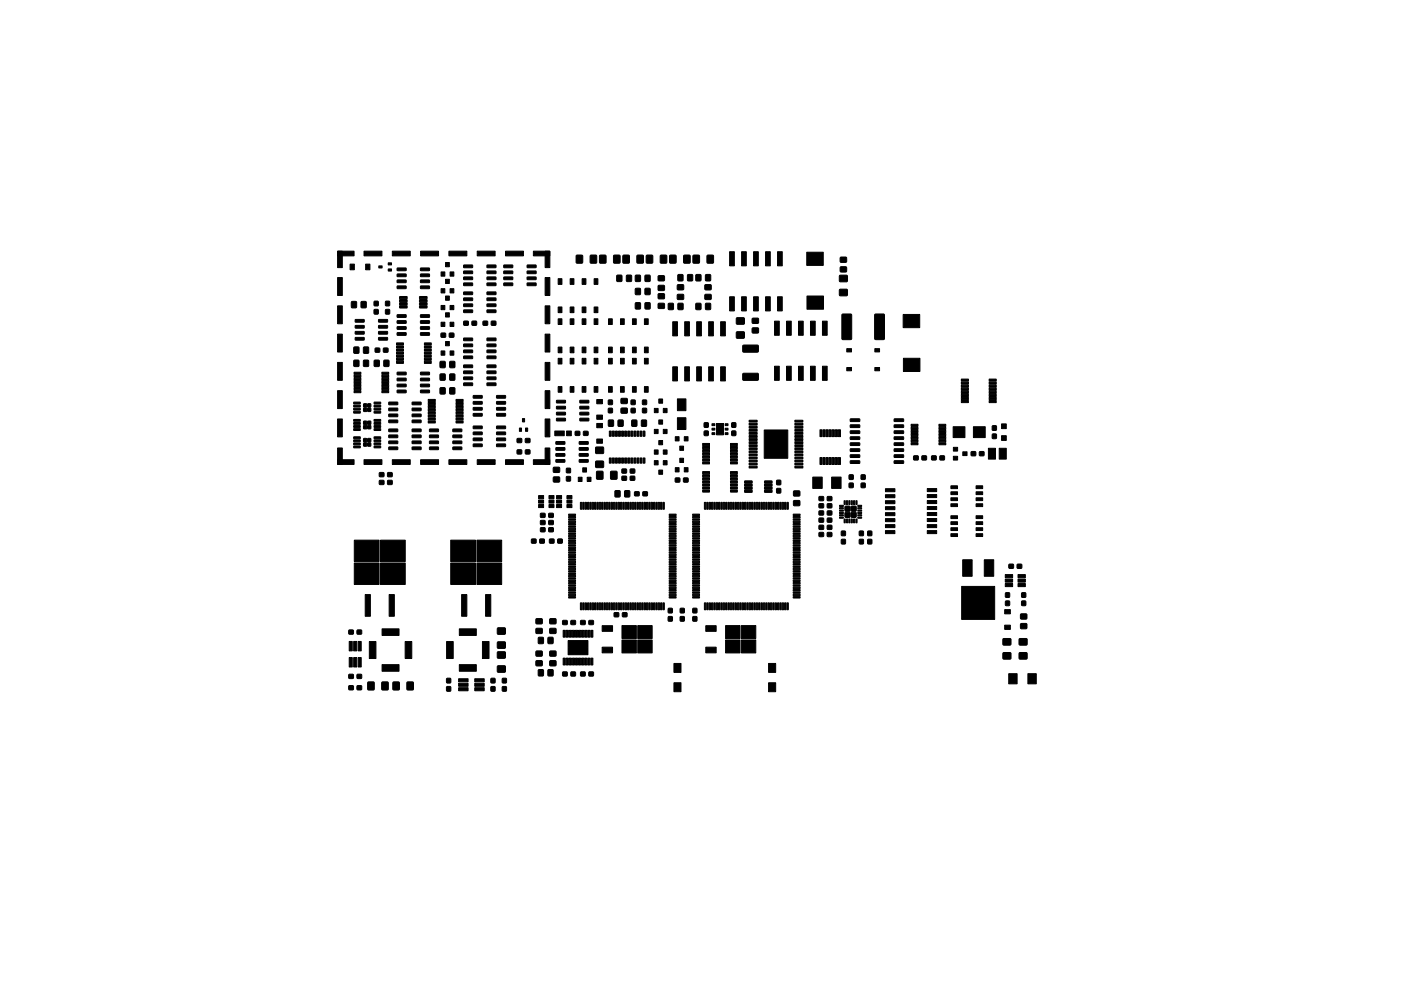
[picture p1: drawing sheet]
<svg xmlns="http://www.w3.org/2000/svg" width="297mm" height="210mm" viewBox="0 0 297 210" stroke-linecap="round" stroke-linejoin="round" font-family="sans-serif">
<g fill="#000" stroke="#000" stroke-width=".21">
<path d="M71.6 53.3h1v3.5h-1zM74.2 56h.9v1.2h-.9zM71.6 53.3h3.5v1h-3.5zM77.5 56h.9v1.2h-.9zM77.2 53.3h3.8v1h-3.8zM80.3 56.4h.7v.5h-.7zM82.3 55.8h.7v.4h-.7zM82.3 57.1h.7v.4h-.7zM84.2 59.4h1.8l.1 .5-.1 .1h-1.7zM84.2 58.2l1.8-.1 .1 .5-.1 .1h-1.7zM84.2 56.9l1.8-.1 .1 .5-.1 .1h-1.7zM83.2 53.3h3.8v1h-3.8z"/>
<path d="M89.2 56.9l1.8-.1 .1 .5-.2 .1h-1.6zM89.2 58.2l1.8-.1 .1 .5-.2 .1h-1.6zM89.2 59.4h1.8l.1 .5-.2 .1h-1.6zM89.2 53.3h3.8v1h-3.8zM93.5 57.7h.8v.9h-.8zM94.5 55.7h.8v.9h-.8zM95.4 57.7h.8v.9h-.8zM95.2 53.3h3.8v1h-3.8zM98.3 58.8h1.8l.1 .4-.1 .1h-1.7zM98.3 57.5h1.8l.1 .5-.1 .1h-1.7zM98.3 56.3l1.8-.1 .1 .5-.1 .1h-1.7zM101.2 53.3h3.8v1h-3.8z"/>
<path d="M103.3 56.3l1.8-.1 .1 .5-.2 .1h-1.7zM103.3 57.5h1.8l.1 .5-.2 .1h-1.7zM103.3 58.8h1.8l.1 .4-.2 .1h-1.7zM106.8 58.8h1.8l.1 .4-.1 .1h-1.7zM106.8 57.5h1.8l.1 .5-.1 .1h-1.7zM106.8 56.3l1.8-.1 .1 .5-.1 .1h-1.7zM107.2 53.3h3.8v1h-3.8zM111.8 56.3l1.8-.1 .1 .5-.1 .1h-1.7zM111.8 57.5h1.8l.1 .5-.1 .1h-1.7zM111.8 58.8h1.8l.1 .4-.1 .1h-1.7zM115.6 53.3h1v3.5h-1zM113.1 53.3h3.5v1h-3.5z"/>
<path d="M122.2 54.2h1.3v1.6h-1.3zM125.2 54.2h1.3l-.1 1.6h-1.2zM127.2 54.2h1.3l-.1 1.6h-1.3zM130.1 54.2h1.3v1.6h-1.3zM130.8 58.4h1v1.3h-1zM132.1 54.2h1.3v1.6h-1.3zM132.9 58.4h1l-.1 1.3h-1zM134.7 58.4h1.1l-.1 1.3h-1zM135.1 54.2h1.3l-.1 1.6h-1.2zM136.8 58.4h1v1.3h-1zM137.1 54.2h1.3l-.1 1.6h-1.3zM139.6 58.5h1.2l.1 1-1.3 .1z"/>
<path d="M140 54.2h1.3v1.6h-1.3zM142 54.2h1.3v1.6h-1.3zM143.8 58.3h1l-.1 1.3-1-.1zM145 54.2h1.3v1.6h-1.3zM145.8 58.3h1v1.3l-1-.1zM147 54.2h1.3l-.1 1.6h-1.2zM147.6 58.3h1v1.3l-1-.1zM149.6 58.3h1v1.3l-1-.1zM149.9 54.2h1.3v1.6h-1.3zM154.7 53.4h1v3h-1zM157.2 53.4h1v3h-1zM159.8 53.4h1v3h-1z"/>
<path d="M162.3 53.4h1v3h-1zM164.9 53.4h1v3h-1zM171 53.5h3.5v2.8h-3.5zM178.2 54.6h1.2l.1 1h-1.3zM178.2 56.7l1.2-.1 .1 1-1.3 .1zM178 58.4h1.6v1.3h-1.6zM71.6 58.9h1v3.8h-1zM71.6 64.9h1v3.8h-1zM71.6 70.9h1v3.8h-1zM75.1 79h1.4v.4h-1.4zM74.5 64h1.1l-.1 1.3-1-.1zM75.1 73.7h1l-.1 1.2h-1z"/>
<path d="M75.1 76.5h1l-.1 1.2h-1zM75.3 71.6h1.8l.1 .5-.1 .1h-1.7zM75.3 70.4l1.8-.1 .1 .5-.1 .1h-1.7zM75.3 69.1l1.8-.1 .1 .5-.1 .1h-1.7zM75.3 67.8h1.8l.1 .4-.1 .2h-1.7zM76.6 64h1v1.3l-1-.1zM77.1 73.7h1v1.2h-1zM77.1 76.5h1v1.2h-1zM79.4 63.9l.8 .1-.1 .9-.8-.1zM79.4 65.7h.8l-.1 .9h-.8zM79.4 76.5h1v1.2h-1zM79.6 73.9h.9v.8h-.9z"/>
<path d="M81 79h1.4v.4h-1.4zM80.3 67.8h1.8l.1 .4-.1 .2h-1.7zM80.3 69.1l1.8-.1 .1 .5-.1 .1h-1.7zM80.3 70.4l1.8-.1 .1 .5-.1 .1h-1.7zM80.3 71.6h1.8l.1 .5-.1 .1h-1.7zM81.3 73.9h.9v.8h-.9zM81.4 76.5h1v1.2h-1zM81.8 63.9l.8 .1v.9l-.9-.1zM81.8 65.7h.8v.9h-.9zM84.1 76.6h1.4v.5h-1.4zM84.1 76h1.4v.4h-1.4zM84.1 75.3h1.4v.5h-1.4z"/>
<path d="M84.1 74.7h1.4v.4h-1.4zM84.1 74h1.4v.5h-1.4zM84.1 73.4h1.4v.4h-1.4zM84.1 72.7h1.4v.5h-1.4zM84.2 79l1.8-.1 .1 .5-.1 .1h-1.7zM84.2 70.6h1.8l.1 .4-.1 .2h-1.7zM84.2 69.3h1.8l.1 .5-.1 .1h-1.7zM84.2 68.1l1.8-.1 .1 .5-.1 .1h-1.7zM84.2 66.8h1.8l.1 .4-.1 .1h-1.7zM84.2 60.7h1.8l.1 .4-.1 .2h-1.7zM84.7 64.9h1.5l.1 .4-1.5 .1zM84.7 64.2h1.5l.1 .4-1.5 .1z"/>
<path d="M84.7 63.6h1.5l.1 .4-1.5 .1zM84.7 62.9h1.5l.1 .4-1.5 .1zM90 72.7h1.4v.5h-1.4zM90 73.4h1.4v.4h-1.4zM90 74h1.4v.5h-1.4zM90 74.7h1.4v.4h-1.4zM90 75.3h1.4v.5h-1.4zM90 76h1.4v.4h-1.4zM90 76.6h1.4v.5h-1.4zM89 62.9h1.5l.1 .4-1.6 .1zM89 63.6h1.5l.1 .4-1.6 .1zM89 64.2h1.5l.1 .4-1.6 .1z"/>
<path d="M89 64.9h1.5l.1 .4-1.6 .1zM89.2 79l1.8-.1 .1 .5-.2 .1h-1.6zM89.2 66.8h1.8l.1 .4-.2 .1h-1.6zM89.2 68.1l1.8-.1 .1 .5-.2 .1h-1.6zM89.2 69.3h1.8l.1 .5-.2 .1h-1.6zM89.2 70.6h1.8l.1 .4-.2 .2h-1.6zM89.2 60.7h1.8l.1 .4-.2 .2h-1.6zM93.3 76.7h1.1l-.1 1.3-1-.1zM93.3 79.4h1.1l-.1 1.2h-1zM93.5 70.7h.9l.1 .8h-.9zM93.5 68.4h.8v.9h-.8zM93.5 64.8h.8v.9h-.8z"/>
<path d="M93.5 74.5h.8v.9h-.8zM93.5 61.3h.8v.9h-.8zM94.5 66.4h.8v.9h-.8zM94.5 62.8h.8v.9h-.8zM94.5 72.5h.8v.9h-.8zM94.5 59.3h.8v.9h-.8zM95.3 70.7h.9v.8h-.9zM95.4 68.4h.8v.9h-.8zM95.4 64.8h.8v.9h-.8zM95.4 74.5h.8v.9h-.8zM95.4 61.3h.8v.9h-.8zM95.4 76.7h1v1.3l-1-.1z"/>
<path d="M95.4 79.4h1v1.2h-1zM98.4 68.2h.8l.1 .8h-.9zM98.3 65.8l1.8-.1 .1 .5-.1 .1h-1.7zM98.3 64.5h1.8l.1 .4-.1 .2h-1.7zM98.3 63.2h1.8l.1 .5-.1 .1h-1.7zM98.3 62l1.8-.1 .1 .5-.1 .1h-1.7zM98.3 60.1l1.8-.1 .1 .5-.1 .1h-1.7zM98.3 80h1.8l.1 .4-.1 .2h-1.7zM98.3 78.7h1.8l.1 .5-.1 .1h-1.7zM98.3 77.5l1.8-.1 .1 .5-.1 .1h-1.7zM98.3 75.6l1.8-.1 .1 .5-.1 .1h-1.7zM98.3 74.3l1.8-.1 .1 .5-.1 .1h-1.7z"/>
<path d="M98.3 73h1.8l.1 .5-.1 .1h-1.7zM98.3 71.7h1.8l.1 .5-.1 .1h-1.7zM100.1 68.2h.9v.8h-.9zM102.4 68.2h.9l.1 .8h-.9zM104.2 68.2h.9v.8h-.9zM103.3 62l1.8-.1 .1 .5-.2 .1h-1.7zM103.3 63.2h1.8l.1 .5-.2 .1h-1.7zM103.3 64.5h1.8l.1 .4-.2 .2h-1.7zM103.3 65.8l1.8-.1 .1 .5-.2 .1h-1.7zM103.3 60.1l1.8-.1 .1 .5-.2 .1h-1.7zM103.3 77.5l1.8-.1 .1 .5-.2 .1h-1.7zM103.3 78.7h1.8l.1 .5-.2 .1h-1.7z"/>
<path d="M103.3 80h1.8l.1 .4-.2 .2h-1.7zM103.3 71.7h1.8l.1 .5-.2 .1h-1.7zM103.3 73h1.8l.1 .5-.2 .1h-1.7zM103.3 74.3l1.8-.1 .1 .5-.2 .1h-1.7zM103.3 75.6l1.8-.1 .1 .5-.2 .1h-1.7zM106.8 60.1l1.8-.1 .1 .5-.1 .1h-1.7zM111.8 60.1l1.8-.1 .1 .5-.1 .1h-1.7zM115.6 58.9h1v3.8h-1zM115.6 70.9h1v3.8h-1zM115.6 64.9h1v3.8h-1zM118.3 76h.8v1.2h-.8zM118.3 67.6h.8v1.2h-.8z"/>
<path d="M118.3 73.6h.8v1.2h-.8zM118.3 59.1h.8v1.2h-.8zM118.3 65.1h.8v1.2h-.8zM120.9 76h.8v1.2h-.8zM120.9 67.6h.8v1.2h-.8zM120.9 73.6h.8v1.2h-.8zM120.9 59.1h.8v1.2h-.8zM120.9 65.1h.8v1.2h-.8zM123.4 76h.8v1.2h-.8zM123.4 67.6h.8v1.2h-.8zM123.4 73.6h.8v1.2h-.8zM123.4 59.1h.8v1.2h-.8z"/>
<path d="M123.4 65.1h.8v1.2h-.8zM126 76h.8v1.2h-.8zM126 67.6h.8v1.2h-.8zM126 73.6h.8v1.2h-.8zM126 59.1h.8v1.2h-.8zM126 65.1h.8v1.2h-.8zM129 67.6h.8v1.2h-.8zM129 73.6h.8v1.2h-.8zM129 76h.8v1.2h-.8zM131.6 67.6h.8v1.2h-.8zM131.6 73.6h.8v1.2h-.8zM131.6 76h.8v1.2h-.8z"/>
<path d="M134.1 67.6h.8v1.2h-.8zM134.1 73.6h.8v1.2h-.8zM134.1 76h.8v1.2h-.8zM134.7 61.2h1.1l-.1 1.3h-1zM134.7 64.3h1.1l-.1 1.2h-1zM136.6 67.6h.8v1.2h-.8zM136.6 73.6h.8v1.2h-.8zM136.6 76h.8v1.2h-.8zM136.8 61.2h1v1.3h-1zM136.8 64.3h1v1.2h-1zM139.6 60.6h1.2l.1 1h-1.3zM139.6 64.4h1.2l.1 1h-1.3z"/>
<path d="M139.6 62.3h1.2l.1 1-1.3 .1zM141.7 64.4h1v1.3l-1-.1zM142.6 77.8h1v3h-1zM142.6 68.3h1v3h-1zM143.8 64.4h1v1.3l-1-.1zM143.6 60.4h1.3v1l-1.2 .1zM143.6 62.5h1.3v1h-1.2zM145.2 77.8h1v3h-1zM145.2 68.3h1v3h-1zM147.6 64.4h1v1.3l-1-.1zM147.7 77.8h1v3h-1zM147.7 68.3h1v3h-1z"/>
<path d="M149.6 64.4h1v1.3l-1-.1zM149.5 62.5h1.2l.1 1h-1.3zM149.5 60.4h1.2l.1 1-1.3 .1zM150.2 77.8h1v3h-1zM150.2 68.3h1v3h-1zM152.8 77.8h1v3h-1zM152.8 68.3h1v3h-1zM154.7 63h1v3h-1zM156.2 67.5l1.6-.1v1.3l-1.6 .1zM156.2 70.4h1.6v1.3h-1.6zM157.2 63h1v3h-1zM157.5 79.3l3.2-.1 .1 .2v1.2l-.2 .1h-3l-.1-.2z"/>
<path d="M157.5 73.3l3.2-.1 .1 .2v1.2l-.2 .1h-3l-.1-.2zM159.5 69.6h1.3v1h-1.3zM159.5 67.6l1.3-.1v1l-1.3 .1zM159.8 63h1v3h-1zM162.3 63h1v3h-1zM164.2 77.7h1v3h-1zM164.2 68.1h1v3h-1zM164.9 63h1v3h-1zM166.8 77.7h1v3h-1zM166.8 68.1h1v3h-1zM169.3 77.7h1v3h-1zM169.3 68.1h1v3h-1z"/>
<path d="M171.1 62.8h3.5v2.8h-3.5zM171.8 77.7h1v3h-1zM171.8 68.1h1v3h-1zM174.4 77.7h1v3h-1zM174.4 68.1h1v3h-1zM178 61.4h1.6v1.3h-1.6zM179.5 78h1v.7h-1zM179.5 74h1v.7h-1zM178.6 66.7l1.8-.1 .2 .2v5l-.2 .3h-1.7l-.2-.2zM185.5 74h1v.7h-1zM185.5 78h1v.7h-1zM185.5 66.7l1.8-.1 .2 .2v5l-.1 .3h-1.7l-.3-.2z"/>
<path d="M191.5 66.7h3.5v2.8h-3.5zM191.5 76h3.5v2.8h-3.5zM71.6 95h1v3.5h-1zM71.6 82.9h1v3.8h-1zM71.6 88.9h1v3.8h-1zM71.6 76.9h1v3.8h-1zM75.1 82.9h1.4v.4h-1.4zM75.1 82.2h1.4v.5h-1.4zM75.1 81.6h1.4v.4h-1.4zM75.1 80.9h1.4v.5h-1.4zM75.1 80.3h1.4v.4h-1.4zM75.1 79.6h1.4v.5h-1.4z"/>
<path d="M71.6 97.5h3.5v1h-3.5zM75 91l1.3-.1 .1 .4h-1.3zM75 90.3h1.3l.1 .3-1.3 .1zM75 89.7l1.3-.1 .1 .4h-1.3zM75 89h1.3l.1 .3-1.3 .1zM75 94.7l1.3-.1 .1 .3-1.3 .1zM75 94h1.3l.1 .3-1.3 .1zM75 93.4l1.3-.1 .1 .3-1.3 .1zM75 92.7h1.3l.1 .3-1.3 .1zM75 87.3h1.3l.1 .3-1.3 .1zM75 86.6h1.3l.1 .3-1.3 .1zM75 86h1.3l.1 .3-1.3 .1z"/>
<path d="M75 85.3h1.3l.1 .3-1.3 .1zM77.1 90.3h.6v.7h-.6zM77.1 89.4h.6v.6h-.6zM77.1 94h.6v.6h-.6zM77.1 93.1h.6v.6h-.6zM77.1 86.6h.6v.7h-.6zM77.1 85.7h.6v.7h-.6zM78 90.3h.6v.7h-.6zM78 89.4h.6v.6h-.6zM78 94h.6v.6h-.6zM78 93.1h.6v.6h-.6zM78 86.6h.6v.7h-.6z"/>
<path d="M78 85.7h.6v.7h-.6zM79.3 89h1.3l.1 .3-1.3 .1zM79.3 89.7l1.3-.1 .1 .4h-1.3zM79.3 90.3h1.3l.1 .3-1.3 .1zM79.3 91l1.3-.1 .1 .4h-1.3zM79.3 92.7h1.3l.1 .3-1.3 .1zM79.3 93.4l1.3-.1 .1 .3-1.3 .1zM79.3 94h1.3l.1 .3-1.3 .1zM79.3 94.7l1.3-.1 .1 .3-1.3 .1zM79.3 85.3h1.3l.1 .3-1.3 .1zM79.3 86h1.3l.1 .3-1.3 .1zM79.3 86.6h1.3l.1 .3-1.3 .1z"/>
<path d="M79.3 87.3h1.3l.1 .3-1.3 .1zM81 79.6h1.4v.5h-1.4zM81 80.3h1.4v.4h-1.4zM81 80.9h1.4v.5h-1.4zM81 81.6h1.4v.4h-1.4zM81 82.2h1.4v.5h-1.4zM81 82.9h1.4v.4h-1.4zM77.2 97.5h3.8v1h-3.8zM82.4 89.1h1.8l.1 .5-.1 .1h-1.7zM82.4 87.9l1.8-.1 .1 .5-.1 .1h-1.7zM82.4 86.6h1.8l.1 .4-.1 .2h-1.7zM82.4 85.3h1.8l.1 .5-.1 .1h-1.7z"/>
<path d="M82.4 94.9l1.8-.1 .1 .5-.1 .1h-1.7zM82.4 93.6h1.8l.1 .4-.1 .1h-1.7zM82.4 92.3h1.8l.1 .5-.1 .1h-1.7zM82.4 91.1l1.8-.1 .1 .5-.1 .1h-1.7zM84.2 82.8h1.8l.1 .4-.1 .2-1.7-.1zM84.2 81.5h1.8l.1 .5-.1 .1h-1.7zM84.2 80.3l1.8-.1 .1 .5-.1 .1h-1.7zM83.2 97.5h3.8v1h-3.8zM87.4 85.3h1.8l.1 .5-.1 .1h-1.7zM87.4 86.6h1.8l.1 .4-.1 .2h-1.7zM87.4 87.9l1.8-.1 .1 .5-.1 .1h-1.7zM87.4 89.1h1.8l.1 .5-.1 .1h-1.7z"/>
<path d="M87.4 91.1l1.8-.1 .1 .5-.1 .1h-1.7zM87.4 92.3h1.8l.1 .5-.1 .1h-1.7zM87.4 93.6h1.8l.1 .4-.1 .1h-1.7zM87.4 94.9l1.8-.1 .1 .5-.1 .1h-1.7zM90.8 89.3h1.5v.4h-1.5zM90.8 88.6h1.5v.5h-1.5zM90.8 88h1.5v.4h-1.5zM90.8 87.3h1.5v.5h-1.5zM90.8 86.7h1.5v.4h-1.5zM90.8 86h1.5v.5h-1.5zM90.8 85.4h1.5v.4h-1.5zM90.8 84.7h1.5v.5h-1.5z"/>
<path d="M89.2 80.3l1.8-.1 .1 .5-.2 .1h-1.6zM89.2 81.5h1.8l.1 .5-.2 .1h-1.6zM89.2 82.8h1.8l.1 .4-.2 .2-1.6-.1zM91.1 94.9l1.8-.1 .1 .5-.1 .1h-1.7zM91.1 93.6h1.8l.1 .4-.1 .1h-1.7zM91.1 92.3h1.8l.1 .5-.1 .1h-1.7zM91.1 91.1l1.8-.1 .1 .5-.1 .1h-1.7zM89.2 97.5h3.8v1h-3.8zM93.3 82.3h1.1l-.1 1.3-1-.1zM95.4 82.3h1v1.3l-1-.1zM96.7 84.7h1.5v.5h-1.5zM96.7 85.4h1.5v.4h-1.5z"/>
<path d="M96.7 86h1.5v.5h-1.5zM96.7 86.7h1.5v.4h-1.5zM96.7 87.3h1.5v.5h-1.5zM96.7 88h1.5v.4h-1.5zM96.7 88.6h1.5v.5h-1.5zM96.7 89.3h1.5v.4h-1.5zM96 91.1l1.8-.1 .1 .5-.1 .1h-1.7zM96 92.3h1.8l.1 .5-.1 .1h-1.7zM96 93.6h1.8l.1 .4-.1 .1h-1.7zM96 94.9l1.8-.1 .1 .5-.1 .1h-1.7zM95.2 97.5h3.8v1h-3.8zM98.3 81.3l1.8-.1 .1 .5-.1 .1h-1.7z"/>
<path d="M100.4 87.7h1.7l.2 .5-.2 .1h-1.7zM100.4 86.5l1.7-.1 .2 .5-.2 .1h-1.7zM100.4 85.2h1.7l.2 .4-.2 .2h-1.7zM100.4 83.9h1.7l.2 .5-.2 .1h-1.7zM100.4 94.2h1.7l.2 .5-.2 .1h-1.7zM100.4 93l1.7-.1 .2 .5-.2 .1h-1.7zM100.4 91.7l1.7-.1 .2 .5-.2 .1h-1.7zM100.4 90.4h1.7l.2 .5-.2 .1h-1.7zM101.2 97.5h3.8v1h-3.8zM103.3 81.3l1.8-.1 .1 .5-.2 .1h-1.7zM105.3 83.9h1.8l.1 .5-.1 .1h-1.7zM105.3 85.2h1.8l.1 .4-.1 .2h-1.7z"/>
<path d="M105.3 86.5l1.8-.1 .1 .5-.1 .1h-1.7zM105.3 87.7h1.8l.1 .5-.1 .1h-1.7zM105.3 90.4h1.8l.1 .5-.1 .1h-1.7zM105.3 91.7l1.8-.1 .1 .5-.1 .1h-1.7zM105.3 93l1.8-.1 .1 .5-.1 .1h-1.7zM105.3 94.2h1.8l.1 .5-.1 .1h-1.7zM110.1 90.8h.5v.7h-.5zM109.7 93.1l.9-.1v.9h-.9zM109.7 95.5h.9v.8h-.9zM110.8 88.8h.4v.7h-.4zM107.2 97.5h3.8v1h-3.8zM111.4 90.8h.5v.7h-.5z"/>
<path d="M111.4 93.1l.9-.1v.9h-.9zM111.4 95.5h.9v.8h-.9zM115.6 82.9h1v3.8h-1zM115.6 76.9h1v3.8h-1zM115.6 88.9h1v3.8h-1zM115.6 95h1v3.5h-1zM113.1 97.5h3.5v1h-3.5zM117.6 91.4h2v1h-2zM118.3 82h.8v1.2h-.8zM117.4 99.2h1.2v1h-1.2zM117.9 97.5h1.8l.1 .5-.2 .1h-1.6zM117.9 96.3l1.8-.1 .1 .5-.2 .1h-1.6z"/>
<path d="M117.9 95l1.8-.1 .1 .5-.2 .1h-1.6zM117.9 93.7h1.8l.1 .5-.2 .1h-1.6zM118 88.8l1.8-.1 .1 .5-.1 .1h-1.7zM118 87.5h1.8l.1 .4-.1 .2-1.7-.1zM118 86.2h1.8l.1 .5-.1 .1h-1.7zM118 85l1.8-.1 .1 .5-.1 .1h-1.7zM120.1 91.4h1v1h-1zM120.1 99.4h.8v.9h-.8zM120.9 82h.8v1.2h-.8zM122 91.5h.9v.8l-.9 .1zM123.4 82h.8v1.2h-.8zM123.7 91.5h.9l.1 .8-.9 .1z"/>
<path d="M122.8 93.7h1.8l.1 .5-.1 .1h-1.7zM122.8 95l1.8-.1 .1 .5-.1 .1h-1.7zM122.8 96.3l1.8-.1 .1 .5-.1 .1h-1.7zM122.8 97.5h1.8l.1 .5-.1 .1h-1.7zM123 85l1.7-.1 .2 .5-.2 .1h-1.7zM123 86.2h1.7l.2 .5-.2 .1h-1.7zM123 87.5h1.7l.2 .4-.2 .2-1.7-.1zM123 88.8l1.7-.1 .2 .5-.2 .1h-1.7zM126 82h.8v1.2h-.8zM126.5 88.1h1.2v.9h-1.2zM126.5 84.8h1.2v.9h-1.2zM126.5 100h1.3v1.7l-1.3-.1z"/>
<path d="M126.5 89.8h1.2v.9h-1.2zM126.5 93.1h1.2v.9h-1.2zM126.3 97.9h1.6v1.2l-1.6 .1zM126.3 94.9h1.6v1.3h-1.6zM129 82h.8v1.2h-.8zM129.2 91.5h.4v1.1h-.4zM129.2 97.2h.4v1.1h-.4zM129 84.9h.8v.9h-.8zM129 86.6l.8 .1v.9l-.8-.1zM129 89.2h1v1.2h-1zM129.8 91.5h.4v1.1h-.4zM129.8 97.2h.4v1.1h-.4z"/>
<path d="M129.5 100h1.3v1.7l-1.3-.1zM130.5 91.5h.4v1.1h-.4zM130.5 97.2h.4v1.1h-.4zM131.1 91.5h.4v1.1h-.4zM131.1 97.2h.4v1.1h-.4zM131.6 82h.8v1.2h-.8zM131.1 89.2h1v1.2h-1zM131.8 91.5h.4v1.1h-.4zM131.8 97.2h.4v1.1h-.4zM131.9 99.5h.9v.8l-.9 .1zM131.7 84.6h1.2l.1 1h-1.3zM131.7 86.6h1.2l.1 1h-1.3z"/>
<path d="M132.4 91.5h.4v1.1h-.4zM132.4 97.2h.4v1.1h-.4zM133.1 91.5h.4v1.1h-.4zM133.1 97.2h.4v1.1h-.4zM134.1 82h.8v1.2h-.8zM133.7 91.5h.4v1.1h-.4zM133.7 97.2h.4v1.1h-.4zM133.6 99.5h.9l.1 .8-.9 .1zM133.8 84.9h.9l-.1 .9h-.8zM133.8 86.6l.9 .1-.1 .9-.8-.1zM134.4 91.5h.4v1.1h-.4zM134.4 97.2h.4v1.1h-.4z"/>
<path d="M134 89.2h1v1.2h-1zM135 91.5h.4v1.1h-.4zM135 97.2h.4v1.1h-.4zM135.7 91.5h.4v1.1h-.4zM135.7 97.2h.4v1.1h-.4zM136.6 82h.8v1.2h-.8zM136.3 91.5h.4v1.1h-.4zM136.3 97.2h.4v1.1h-.4zM136 89.2h1.1l-.1 1.2h-1zM136.2 86.6l.9 .1-.1 .9-.8-.1zM136.2 84.9h.9l-.1 .9h-.8zM138.7 97.7h.8v.9h-.8z"/>
<path d="M138.7 86.7h.8v.9h-.8zM138.7 91.1h.8v.9h-.8zM138.7 95.5h.8v.9h-.8zM139.7 99.7h.8v.9h-.8zM139.7 84.7h.8v.9h-.8zM139.7 89.1h.8v.9h-.8zM139.7 93.5h.8v.9h-.8zM140.6 97.7h.8v.9h-.8zM140.6 86.7h.8v.9h-.8zM140.6 91.1h.8v.9h-.8zM140.6 95.5h.8v.9h-.8zM143.2 92.7h.8v.9h-.8z"/>
<path d="M144.1 94.7h.8v.9h-.8zM144.1 97.2h.8v.9h-.8zM145.1 92.7h.8v.9h-.8zM143.6 84.6h1.8v2.5h-1.8zM143.6 88.6h1.8v2.5h-1.8zM149.3 91.5h.9l-.1 .9h-.8zM149.3 89.7h.9l-.1 .9h-.8zM149 98h1.4v.4h-1.4zM149 97.3h1.4v.5h-1.4zM149 96.7h1.4v.4h-1.4zM149 96h1.4v.5h-1.4zM149 95.4h1.4v.4h-1.4z"/>
<path d="M149 94.7h1.4v.5h-1.4zM149 94.1h1.4v.4h-1.4zM151 91.8h.6v.4h-.6zM151 90.9h.6v.4h-.6zM151 89.9h.6v.4h-.6zM151.9 89.9h1.5v2.4h-1.5zM153.8 89.9h.6v.4h-.6zM153.8 90.9h.6v.4h-.6zM153.8 91.8h.6v.4h-.6zM155.2 91.5h.8v.9h-.8zM155.2 89.7h.8v.9h-.8zM154.9 94.1h1.4v.4h-1.4z"/>
<path d="M154.9 94.7h1.4v.5h-1.4zM154.9 95.4h1.4v.4h-1.4zM154.9 96h1.4v.5h-1.4zM154.9 96.7h1.4v.4h-1.4zM154.9 97.3h1.4v.5h-1.4zM154.9 98h1.4v.4h-1.4zM158.8 98.9h1.7v.4h-1.7zM158.8 98.3h1.7v.3h-1.7zM158.8 97.6h1.7v.4h-1.7zM158.8 97h1.7v.3h-1.7zM158.8 96.3h1.7v.4h-1.7zM158.8 95.7h1.7v.3h-1.7z"/>
<path d="M158.8 95h1.7v.4h-1.7zM158.8 94.4h1.7v.3h-1.7zM158.8 93.7h1.7v.4h-1.7zM158.8 93.1h1.7v.3h-1.7zM158.8 92.4h1.7v.4h-1.7zM158.8 91.8h1.7v.3h-1.7zM158.8 91.1h1.7v.4h-1.7zM158.8 90.5h1.7v.3h-1.7zM158.8 89.8h1.7v.4h-1.7zM158.8 89.2h1.7v.3h-1.7zM162 91.2h5v6h-5zM168.5 97.6h1.7v.4h-1.7z"/>
<path d="M168.5 91.1h1.7v.4h-1.7zM168.5 89.2h1.7v.3h-1.7zM168.5 95.7h1.7v.3h-1.7zM168.5 96.3h1.7v.4h-1.7zM168.5 98.9h1.7v.4h-1.7zM168.5 91.8h1.7v.3h-1.7zM168.5 90.5h1.7v.3h-1.7zM168.5 98.3h1.7v.3h-1.7zM168.5 97h1.7v.3h-1.7zM168.5 93.1h1.7v.3h-1.7zM168.5 94.4h1.7v.3h-1.7zM168.5 92.4h1.7v.4h-1.7z"/>
<path d="M168.5 93.7h1.7v.4h-1.7zM168.5 89.8h1.7v.4h-1.7zM168.5 95h1.7v.4h-1.7zM173.8 91.2h.5v1.4h-.5zM173.8 97.1h.5v1.4h-.5zM174.5 91.2h.4v1.4h-.4zM174.5 97.1h.4v1.4h-.4zM175.1 91.2h.5v1.4h-.5zM175.1 97.1h.5v1.4h-.5zM175.8 91.2h.4v1.4h-.4zM175.8 97.1h.4v1.4h-.4zM176.4 91.2h.5v1.4h-.5z"/>
<path d="M176.4 97.1h.5v1.4h-.5zM177.1 91.2h.4v1.4h-.4zM177.1 97.1h.4v1.4h-.4zM177.7 91.2h.5v1.4h-.5zM177.7 97.1h.5v1.4h-.5zM180.3 97.8l1.9-.1 .1 .5-.1 .1h-1.8zM180.3 96.5h1.9l.1 .4-.1 .2h-1.8zM180.3 95.2h1.9l.1 .5-.1 .1h-1.8zM180.3 94l1.9-.1 .1 .5-.1 .1h-1.8zM180.3 92.7h1.9l.1 .4-.1 .2h-1.8zM180.3 91.4h1.9l.1 .5-.1 .1h-1.8zM180.3 90.2l1.9-.1 .1 .5-.1 .1h-1.8z"/>
<path d="M180.3 88.9h1.9l.1 .4-.1 .1h-1.8zM189.6 88.9h1.9l.1 .4-.1 .1h-1.8zM189.6 90.2l1.9-.1 .1 .5-.1 .1h-1.8zM189.6 91.4h1.9l.1 .5-.1 .1h-1.8zM189.6 92.7h1.9l.1 .4-.1 .2h-1.8zM189.6 94l1.9-.1 .1 .5-.1 .1h-1.8zM189.6 95.2h1.9l.1 .5-.1 .1h-1.8zM189.6 96.5h1.9l.1 .4-.1 .2h-1.8zM189.6 97.8l1.9-.1 .1 .5-.1 .1h-1.8zM193.2 93.9h1.4v.5h-1.4zM193.2 93.3h1.4v.4h-1.4zM193.2 92.6h1.4v.5h-1.4z"/>
<path d="M193.2 92h1.4v.4h-1.4zM193.2 91.3h1.4v.5h-1.4zM193.2 90.7h1.4v.4h-1.4zM193.2 90h1.4v.5h-1.4zM193.7 96.7h.9l.1 .8-.9 .1zM195.5 96.7h.9v.8l-.9 .1zM197.6 96.7h.8l.1 .8-.9 .1zM199.1 90h1.4v.5h-1.4zM199.1 90.7h1.4v.4h-1.4zM199.1 91.3h1.4v.5h-1.4zM199.1 92h1.4v.4h-1.4zM199.1 92.6h1.4v.5h-1.4z"/>
<path d="M199.1 93.3h1.4v.4h-1.4zM199.1 93.9h1.4v.5h-1.4zM199.3 96.7h.9v.8l-.9 .1zM202.1 90.5h2.5v2.3h-2.5zM202.1 96.8h.9v.8h-.9zM202.1 94.9h.9v.8h-.9zM203.8 85h1.5v.4h-1.5zM203.8 84.3h1.5v.5h-1.5zM203.8 83.7h1.5v.4h-1.5zM203.8 83h1.5v.5h-1.5zM203.8 82.4h1.5v.4h-1.5zM203.8 81.7h1.5v.5h-1.5z"/>
<path d="M203.8 81.1h1.5v.4h-1.5zM203.8 80.4h1.5v.5h-1.5zM204.1 95.9h.9v.8h-.9zM206.4 90.5h2.5v2.3h-2.5zM205.9 95.9l.9-.1 .1 .8-.9 .1zM207.7 95.9l.9-.1v.8l-.9 .1zM209.7 80.4h1.5v.5h-1.5zM209.7 81.1h1.5v.4h-1.5zM209.7 81.7h1.5v.5h-1.5zM209.7 82.4h1.5v.4h-1.5zM209.7 83h1.5v.5h-1.5zM209.7 83.7h1.5v.4h-1.5z"/>
<path d="M209.7 84.3h1.5v.5h-1.5zM209.7 85h1.5v.4h-1.5zM209.6 95.1h1.5v2.3h-1.5zM210.4 90.4h.8v.9h-.8zM210.4 92.1h.8v.9h-.8zM211.8 95.1h1.5v2.3h-1.5zM212.4 89.9h1v1h-1zM212.4 92.4h1v1h-1zM75.1 114.6h5.3v4.6h-5.3zM80.5 100.3h.9v.8h-.9zM80.5 102l.9-.1v.8l-.9 .1zM82.2 100.3h.9v.8h-.9z"/>
<path d="M82.2 102l.9-.1v.8l-.9 .1zM80.7 114.6h5.2v4.6h-5.2zM95.6 114.6h5.2v4.6h-5.2zM101.1 114.6h5.3v4.6h-5.3zM112.7 114.4h.9v.8h-.9zM114.2 107h1.1v.7h-1.1zM114.2 106.1h1.1v.6h-1.1zM114.2 105.1h1.1v.7h-1.1zM114.5 114.4h.9v.8h-.9zM114.6 112h.9v.8h-.9zM114.6 110.5l.9-.1v.9h-.9zM114.6 108.9h.9v.8l-.9 .1z"/>
<path d="M116.4 106.1h1.1v.6h-1.1zM116.4 105.1h1.1v.7h-1.1zM116.4 107h1.1v.7h-1.1zM116.4 112h.9v.8h-.9zM116.4 110.5l.9-.1v.9h-.9zM116.4 108.9h.9v.8l-.9 .1zM116.5 114.4h.9l.1 .8h-1zM118 107h1.1v.7h-1.1zM118 106.1h1.1v.6h-1.1zM118 105.1h1.1v.7h-1.1zM117.4 101.2h1.2v1h-1.2zM118.3 114.4h.9v.8h-.9z"/>
<path d="M120.2 106.1h1.1v.6h-1.1zM120.2 105.1h1.1v.7h-1.1zM120.2 107h1.1v.7h-1.1zM120.1 101.1h.8v1l-.8-.1zM120.6 109.1h1.4v.2l-1.4 .1zM120.6 109.6h1.4v.2l-1.4 .1zM120.6 110.1h1.4v.2l-1.4 .1zM120.6 110.6h1.4v.2l-1.4 .1zM120.6 111.1h1.4v.2l-1.4 .1zM120.6 111.6h1.4v.2l-1.4 .1zM120.6 112.1h1.4v.2l-1.4 .1zM120.6 112.6h1.4v.2l-1.4 .1z"/>
<path d="M120.6 113.1h1.4v.2l-1.4 .1zM120.6 113.6h1.4v.2l-1.4 .1zM120.6 114.1h1.4v.2l-1.4 .1zM120.6 114.6h1.4v.2l-1.4 .1zM120.6 115.1h1.4v.2l-1.4 .1zM120.6 115.6h1.4v.2l-1.4 .1zM120.6 116.1h1.4v.2l-1.4 .1zM120.6 116.6h1.4v.2l-1.4 .1zM120.6 117.1h1.4v.2l-1.4 .1zM120.6 117.6h1.4v.2l-1.4 .1zM120.6 118.1h1.4v.2l-1.4 .1zM120.6 118.6h1.4v.2l-1.4 .1z"/>
<path d="M120.6 119.1h1.4v.2l-1.4 .1zM120.6 119.6h1.4v.2l-1.4 .1zM123.1 106.6h.3l-.1 1.5-.2-.1zM122.6 101.3h.8v.9h-.8zM123.6 106.6h.3l-.1 1.5-.2-.1zM124.1 106.6h.3l-.1 1.5-.2-.1zM123.6 99.3h.8v.9h-.8zM124.6 106.6h.3l-.1 1.5-.2-.1zM125.1 106.6h.3l-.1 1.5-.2-.1zM124.5 101.3h.8v.9h-.8zM125.6 106.6h.3l-.1 1.5-.2-.1zM126.1 106.6h.3l-.1 1.5-.2-.1z"/>
<path d="M126.6 106.6h.3l-.1 1.5-.2-.1zM127.1 106.6h.3l-.1 1.5-.2-.1zM127.6 106.6h.3l-.1 1.5-.2-.1zM128.1 106.6h.3l-.1 1.5-.2-.1zM128.6 106.6h.3l-.1 1.5-.2-.1zM129.1 106.6h.3l-.1 1.5-.2-.1zM129.6 106.6h.3l-.1 1.5-.2-.1zM130.1 106.6h.3l-.1 1.5-.2-.1zM130.6 106.6h.3l-.1 1.5-.2-.1zM130.4 104.1l1 .1v1.2h-1zM131.1 106.6h.3l-.1 1.5-.2-.1zM131.6 106.6h.3l-.1 1.5-.2-.1z"/>
<path d="M132.1 106.6h.3l-.1 1.5-.2-.1zM131.9 101.1l.9-.1v.9h-.9zM132.6 106.6h.3l-.1 1.5-.2-.1zM133.1 106.6h.3l-.1 1.5-.2-.1zM132.5 104.1l1 .1v1.2h-1zM133.6 106.6h.3l-.1 1.5-.2-.1zM134.1 106.6h.3l-.1 1.5-.2-.1zM133.6 101.1l.9-.1 .1 .9h-.9zM134.6 106.6h.3l-.1 1.5-.2-.1zM135.1 106.6h.3l-.1 1.5-.2-.1zM134.6 104.4l.9-.1v.9h-.9zM135.6 106.6h.3l-.1 1.5-.2-.1z"/>
<path d="M136.1 106.6h.3l-.1 1.5-.2-.1zM136.6 106.6h.3l-.1 1.5-.2-.1zM136.3 104.4l.9-.1 .1 .9h-1zM137.1 106.6h.3l-.1 1.5-.2-.1zM137.6 106.6h.3l-.1 1.5-.2-.1zM138.1 106.6h.3l-.1 1.5-.2-.1zM138.6 106.6h.3l-.1 1.5-.2-.1zM139.1 106.6h.3l-.1 1.5-.2-.1zM139.6 106.6h.3l-.1 1.5-.2-.1zM140.1 106.6h.3l-.1 1.5-.2-.1zM140.6 106.6h.3l-.1 1.5-.2-.1zM141.9 119.6h1.4l.1 .2-1.5 .1z"/>
<path d="M141.9 119.1h1.4l.1 .2-1.5 .1zM141.9 118.6h1.4l.1 .2-1.5 .1zM141.9 118.1h1.4l.1 .2-1.5 .1zM141.9 117.6h1.4l.1 .2-1.5 .1zM141.9 117.1h1.4l.1 .2-1.5 .1zM141.9 116.6h1.4l.1 .2-1.5 .1zM141.9 116.1h1.4l.1 .2-1.5 .1zM141.9 115.6h1.4l.1 .2-1.5 .1zM141.9 115.1h1.4l.1 .2-1.5 .1zM141.9 114.6h1.4l.1 .2-1.5 .1zM141.9 114.1h1.4l.1 .2-1.5 .1zM141.9 113.6h1.4l.1 .2-1.5 .1z"/>
<path d="M141.9 113.1h1.4l.1 .2-1.5 .1zM141.9 112.6h1.4l.1 .2-1.5 .1zM141.9 112.1h1.4l.1 .2-1.5 .1zM141.9 111.6h1.4l.1 .2-1.5 .1zM141.9 111.1h1.4l.1 .2-1.5 .1zM141.9 110.6h1.4l.1 .2-1.5 .1zM141.9 110.1h1.4l.1 .2-1.5 .1zM141.9 109.6h1.4l.1 .2-1.5 .1zM141.9 109.1h1.4l.1 .2-1.5 .1zM143.2 101.4h.9v.8l-.9 .1zM143.2 99.2h.8v.9h-.8zM144.9 101.4h.9l.1 .8-.9 .1z"/>
<path d="M145.1 99.2h.8v.9h-.8zM146.9 109.1h1.4v.2l-1.4 .1zM146.9 109.6h1.4v.2l-1.4 .1zM146.9 110.1h1.4v.2l-1.4 .1zM146.9 110.6h1.4v.2l-1.4 .1zM146.9 111.1h1.4v.2l-1.4 .1zM146.9 111.6h1.4v.2l-1.4 .1zM146.9 112.1h1.4v.2l-1.4 .1zM146.9 112.6h1.4v.2l-1.4 .1zM146.9 113.1h1.4v.2l-1.4 .1zM146.9 113.6h1.4v.2l-1.4 .1zM146.9 114.1h1.4v.2l-1.4 .1z"/>
<path d="M146.9 114.6h1.4v.2l-1.4 .1zM146.9 115.1h1.4v.2l-1.4 .1zM146.9 115.6h1.4v.2l-1.4 .1zM146.9 116.1h1.4v.2l-1.4 .1zM146.9 116.6h1.4v.2l-1.4 .1zM146.9 117.1h1.4v.2l-1.4 .1zM146.9 117.6h1.4v.2l-1.4 .1zM146.9 118.1h1.4v.2l-1.4 .1zM146.9 118.6h1.4v.2l-1.4 .1zM146.9 119.1h1.4v.2l-1.4 .1zM146.9 119.6h1.4v.2l-1.4 .1zM149.4 106.6h.2v1.5l-.3-.1z"/>
<path d="M149.9 106.6h.2v1.5l-.3-.1zM149 104h1.4v.4h-1.4zM149 103.3h1.4v.5h-1.4zM149 102.7h1.4v.4h-1.4zM149 102h1.4v.5h-1.4zM149 101.4h1.4v.4h-1.4zM149 100.7h1.4v.5h-1.4zM149 100.1h1.4v.4h-1.4zM150.4 106.6h.2v1.5l-.3-.1zM150.9 106.6h.2v1.5l-.3-.1zM151.4 106.6h.2v1.5l-.3-.1zM151.9 106.6h.2v1.5l-.3-.1z"/>
<path d="M152.4 106.6h.2v1.5l-.3-.1zM152.9 106.6h.2v1.5l-.3-.1zM153.4 106.6h.2v1.5l-.3-.1zM153.9 106.6h.2v1.5l-.3-.1zM154.4 106.6h.2v1.5l-.3-.1zM154.9 106.6h.2v1.5l-.3-.1zM155.4 106.6h.2v1.5l-.3-.1zM155.9 106.6h.2v1.5l-.3-.1zM154.9 100.1h1.4v.4h-1.4zM154.9 100.7h1.4v.5h-1.4zM154.9 101.4h1.4v.4h-1.4zM154.9 102h1.4v.5h-1.4z"/>
<path d="M154.9 102.7h1.4v.4h-1.4zM154.9 103.3h1.4v.5h-1.4zM154.9 104h1.4v.4h-1.4zM156.4 106.6h.2v1.5l-.3-.1zM156.9 106.6h.2v1.5l-.3-.1zM157.4 106.6h.2v1.5l-.3-.1zM157.9 106.6h.2v1.5l-.3-.1zM158.4 106.6h.2v1.5l-.3-.1zM158.9 106.6h.2v1.5l-.3-.1zM157.9 104h1.5l.1 .4-1.5 .1zM157.9 103.4l1.5-.1 .1 .4-1.5 .1zM157.9 102.7h1.5l.1 .4-1.5 .1z"/>
<path d="M157.9 102.1l1.5-.1 .1 .4-1.5 .1zM159.4 106.6h.2v1.5l-.3-.1zM159.9 106.6h.2v1.5l-.3-.1zM160.4 106.6h.2v1.5l-.3-.1zM160.9 106.6h.2v1.5l-.3-.1zM161.4 106.6h.2v1.5l-.3-.1zM161.9 106.6h.2v1.5l-.3-.1zM162.4 106.6h.2v1.5l-.3-.1zM162.9 106.6h.2v1.5l-.3-.1zM163.4 106.6h.2v1.5l-.3-.1zM162.1 102.1l1.5-.1 .1 .4-1.5 .1zM162.1 102.7h1.5l.1 .4-1.5 .1z"/>
<path d="M162.1 103.4l1.5-.1 .1 .4-1.5 .1zM162.1 104h1.5l.1 .4-1.5 .1zM163.9 106.6h.2v1.5l-.3-.1zM164.4 106.6h.2v1.5l-.3-.1zM164.9 106.6h.2v1.5l-.3-.1zM164.7 103.7h.8v.9h-.8zM164.7 101.9h.8v.9h-.8zM165.4 106.6h.2v1.5l-.3-.1zM165.9 106.6h.2v1.5l-.3-.1zM166.4 106.6h.2v1.5l-.3-.1zM166.9 106.6h.2v1.5l-.3-.1zM168.3 104.2h1.2l.1 1h-1.3z"/>
<path d="M168.3 106.2h1.2l.1 1-1.3 .1zM168.2 119.6h1.4v.2l-1.4 .1zM168.2 119.1h1.4v.2l-1.4 .1zM168.2 118.6h1.4v.2l-1.4 .1zM168.2 118.1h1.4v.2l-1.4 .1zM168.2 117.6h1.4v.2l-1.4 .1zM168.2 117.1h1.4v.2l-1.4 .1zM168.2 116.6h1.4v.2l-1.4 .1zM168.2 116.1h1.4v.2l-1.4 .1zM168.2 115.6h1.4v.2l-1.4 .1zM168.2 115.1h1.4v.2l-1.4 .1zM168.2 114.6h1.4v.2l-1.4 .1z"/>
<path d="M168.2 114.1h1.4v.2l-1.4 .1zM168.2 113.6h1.4v.2l-1.4 .1zM168.2 113.1h1.4v.2l-1.4 .1zM168.2 112.6h1.4v.2l-1.4 .1zM168.2 112.1h1.4v.2l-1.4 .1zM168.2 111.6h1.4v.2l-1.4 .1zM168.2 111.1h1.4v.2l-1.4 .1zM168.2 110.6h1.4v.2l-1.4 .1zM168.2 110.1h1.4v.2l-1.4 .1zM168.2 109.6h1.4v.2l-1.4 .1zM168.2 109.1h1.4v.2l-1.4 .1zM172.3 101.2h2v2.4h-2z"/>
<path d="M173.7 113h.9v.8h-.9zM173.7 111.5h.9v.8h-.9zM173.7 110l.9-.1v.8l-.9 .1zM173.7 106.9h.9v.8h-.9zM173.7 108.4h.9v.8l-.9 .1zM173.7 105.4h.9v.8h-.9zM175.4 113h.9l.1 .8h-1zM175.4 111.5h.9l.1 .8h-1zM175.4 110l.9-.1 .1 .8-1 .1zM175.4 106.9h.9l.1 .8h-1zM175.4 108.4h.9l.1 .8-1 .1zM175.4 105.4h.9l.1 .8h-1z"/>
<path d="M176.3 101.2h2v2.4h-2zM178 109.7h.8v.2l-.8 .1zM178 109.2h.8v.2l-.8 .1zM178 108.7h.8v.2l-.8 .1zM178 108.2h.8v.2l-.8 .1zM178 107.7h.8v.2l-.8 .1zM178 107.2h.8v.2l-.8 .1zM178.4 114.5h.8v.9h-.8zM178.4 112.7h.8v.9h-.8zM179 110.1l.2 .1v.7h-.2zM179 106.2l.2 .1v.8l-.2-.1zM179.5 110.1l.2 .1v.7h-.2z"/>
<path d="M179.5 106.2l.2 .1v.8l-.2-.1zM179.2 108.7h1v1h-1zM179.2 107.4h1v1h-1zM180 110.1l.2 .1v.7h-.2zM180 106.2l.2 .1v.8l-.2-.1zM180.5 110.1l.2 .1v.7h-.2zM180.5 106.2l.2 .1v.8l-.2-.1zM180.1 102.5h.8v.9h-.9zM180.1 100.8h.8v.9h-.9zM181 110.1l.2 .1v.7h-.2zM181 106.2l.2 .1v.8l-.2-.1zM180.5 108.7h1v1h-1z"/>
<path d="M180.5 107.4h1v1h-1zM181.5 110.1l.2 .1v.7h-.2zM181.5 106.2l.2 .1v.8l-.2-.1zM181.9 107.2h.7l.1 .2-.8 .1zM181.9 107.7h.7l.1 .2-.8 .1zM181.9 108.2h.7l.1 .2-.8 .1zM181.9 108.7h.7l.1 .2-.8 .1zM181.9 109.2h.7l.1 .2-.8 .1zM181.9 109.7h.7l.1 .2-.8 .1zM182.2 114.5h.8v.9h-.8zM182.2 112.7h.8v.9h-.8zM182.6 102.5h.8v.9h-.8z"/>
<path d="M182.6 100.8h.8v.9h-.8zM184 114.5h.8v.9h-.8zM184 112.7h.8v.9h-.8zM187.7 112.6h2v.6h-2zM187.7 103.7h2v.6h-2zM187.7 105h2v.6h-2zM187.7 106.2h2v.7h-2zM187.7 107.5h2v.6h-2zM187.7 108.8h2v.6h-2zM187.7 110h2v.7h-2zM187.7 111.3h2v.6h-2zM196.6 112.6h2v.6h-2z"/>
<path d="M196.6 111.3h2v.6h-2zM196.6 110h2v.7h-2zM196.6 108.7h2v.7h-2zM196.6 107.5h2v.6h-2zM196.6 106.2h2v.6h-2zM196.6 104.9h2v.7h-2zM196.6 103.7h2v.6h-2zM201.6 109.4h1.4v.6h-1.4zM201.6 110.7h1.4v.6h-1.4zM201.6 112h1.4v.6h-1.4zM201.6 113.2h1.4v.6h-1.4zM201.6 103.1h1.4v.6h-1.4z"/>
<path d="M201.6 104.3h1.4v.6h-1.4zM201.6 105.6h1.4v.6h-1.4zM201.6 106.9h1.4v.6h-1.4zM204.1 118.8h2v3.5h-2zM206.9 109.4h1.4v.6h-1.4zM206.9 110.7h1.4v.6h-1.4zM206.9 112h1.4v.6h-1.4zM206.9 113.2h1.4v.6h-1.4zM206.9 103.1h1.4v.6h-1.4zM206.9 104.3h1.4v.6h-1.4zM206.9 105.6h1.4v.6h-1.4zM206.9 106.9h1.4v.6h-1.4z"/>
<path d="M208.7 118.8h2v3.5h-2zM213.9 119.7h.9l.1 .8-.9 .1zM215.7 119.7h.9v.8l-.9 .1zM74 139.5h.7v2h-.7zM74 136.1h.7v2h-.7zM74 133.7h.9v.8h-.9zM75 139.5h.6v2h-.6zM75 136.1h.6v2h-.6zM75.9 139.5h.7v2h-.7zM75.9 136.1h.7v2h-.7zM75.7 133.7h.9l.1 .8h-1zM78.3 136.1h1.4v3.6h-1.4z"/>
<path d="M77.4 126.2h1.1v4.6h-1.1zM75.1 119.5h5.3v4.5h-5.3zM82.5 126.2h1.1v4.6h-1.1zM81 133.4h3.6v1.4h-3.6zM85.9 136.1h1.4v3.6h-1.4zM80.7 119.5h5.2v4.5h-5.2zM94.7 136.1h1.4v3.6h-1.4zM97.4 133.4h3.6v1.4h-3.6zM97.9 126.2h1.1v4.6h-1.1zM95.6 119.5h5.2v4.5h-5.2zM102.3 136.1h1.4v3.6h-1.4zM103 126.2h1.1v4.6h-1.1z"/>
<path d="M101.1 119.5h5.3v4.5h-5.3zM105.5 138.3h1.6v1.3h-1.6zM105.5 133.2h1.6v1.3h-1.6zM105.5 136.2h1.6v1.3h-1.6zM113.7 138.2h1.2v1h-1.2zM113.7 131.3h1.2v1h-1.2zM113.7 133.4l1.2-.1v1l-1.2 .1zM114.2 135.3h1v1.2h-1zM116.2 135.3h1v1.2h-1zM116.6 138.2h1.2l.1 1h-1.3zM116.6 131.3h1.2l.1 1h-1.3zM116.6 133.4l1.2-.1 .1 1-1.3 .1z"/>
<path d="M119.4 139.6h.5v1.5h-.5zM119.4 133.7h.5v1.5h-.5zM120.1 139.6h.4v1.5h-.4zM120.1 133.7h.4v1.5h-.4zM119.3 131.7h.9v.8h-.9zM120.5 135.9h4.2v3h-4.2zM120.6 137.6h1.1v1.2h-1.1zM120.6 136.1h1.1v1.2h-1.1zM120.7 139.6h.5v1.5h-.5zM120.7 133.7h.5v1.5h-.5zM121.4 139.6h.4v1.5h-.4zM121.4 133.7h.4v1.5h-.4z"/>
<path d="M121.1 131.7h.9v.8h-.9zM120.6 120.1h1.4v.2l-1.4 .1zM120.6 120.6h1.4v.2l-1.4 .1zM120.6 121.1h1.4v.2l-1.4 .1zM120.6 121.6h1.4v.2l-1.4 .1zM120.6 122.1h1.4v.2l-1.4 .1zM120.6 122.6h1.4v.2l-1.4 .1zM120.6 123.1h1.4v.2l-1.4 .1zM120.6 123.6h1.4v.2l-1.4 .1zM120.6 124.1h1.4v.2l-1.4 .1zM120.6 124.6h1.4v.2l-1.4 .1zM120.6 125.1h1.4v.2l-1.4 .1z"/>
<path d="M120.6 125.6h1.4v.2l-1.4 .1zM120.6 126.1h1.4v.2l-1.4 .1zM120.6 126.6h1.4v.2l-1.4 .1zM122 137.6h1.1v1.2h-1.1zM122 136.1h1.1v1.2h-1.1zM122 139.6h.5v1.5h-.5zM122 133.7h.5v1.5h-.5zM122.7 139.6h.4v1.5h-.4zM122.7 133.7h.4v1.5h-.4zM123.1 127.9l.3 .1-.1 1.4-.2-.1zM123.3 139.6h.5v1.5h-.5zM123.3 133.7h.5v1.5h-.5z"/>
<path d="M123.4 136.1h1.1v1.2h-1.1zM123.4 137.6h1.1v1.2h-1.1zM123.6 127.9l.3 .1-.1 1.4-.2-.1zM123.1 131.7h.9l.1 .8h-1zM124 139.6h.4v1.5h-.4zM124 133.7h.4v1.5h-.4zM124.1 127.9l.3 .1-.1 1.4-.2-.1zM124.6 139.6h.5v1.5h-.5zM124.6 133.7h.5v1.5h-.5zM124.6 127.9l.3 .1-.1 1.4-.2-.1zM125.3 139.6h.4v1.5h-.4zM125.3 133.7h.4v1.5h-.4z"/>
<path d="M125.1 127.9l.3 .1-.1 1.4-.2-.1zM124.9 131.7h.9v.8h-.9zM125.6 127.9l.3 .1-.1 1.4-.2-.1zM126.1 127.9l.3 .1-.1 1.4-.2-.1zM126.6 127.9l.3 .1-.1 1.4-.2-.1zM127.1 127.9l.3 .1-.1 1.4-.2-.1zM127.7 137.3h2.2v1.2h-2.2zM127.7 132.8h2.2v1.2h-2.2zM127.6 127.9l.3 .1-.1 1.4-.2-.1zM128.1 127.9l.3 .1-.1 1.4-.2-.1zM128.6 127.9l.3 .1-.1 1.4-.2-.1zM129.1 127.9l.3 .1-.1 1.4-.2-.1z"/>
<path d="M129.6 127.9l.3 .1-.1 1.4-.2-.1zM130.1 127.9l.3 .1-.1 1.4-.2-.1zM130.6 127.9l.3 .1-.1 1.4-.2-.1zM130.2 130h.9l.1 .8h-.9zM131.1 127.9l.3 .1-.1 1.4-.2-.1zM131.6 127.9l.3 .1-.1 1.4-.2-.1zM131.9 135.8h3v2.7h-3zM131.9 132.7h3v2.8h-3zM132.1 127.9l.3 .1-.1 1.4-.2-.1zM132 130h.9v.8h-.9zM132.6 127.9l.3 .1-.1 1.4-.2-.1zM133.1 127.9l.3 .1-.1 1.4-.2-.1z"/>
<path d="M133.6 127.9l.3 .1-.1 1.4-.2-.1zM134.1 127.9l.3 .1-.1 1.4-.2-.1zM134.6 127.9l.3 .1-.1 1.4-.2-.1zM135.2 132.7h3.1v2.8h-3.1zM135.2 135.8h3.1v2.7h-3.1zM135.1 127.9l.3 .1-.1 1.4-.2-.1zM135.6 127.9l.3 .1-.1 1.4-.2-.1zM136.1 127.9l.3 .1-.1 1.4-.2-.1zM136.6 127.9l.3 .1-.1 1.4-.2-.1zM137.1 127.9l.3 .1-.1 1.4-.2-.1zM137.6 127.9l.3 .1-.1 1.4-.2-.1zM138.1 127.9l.3 .1-.1 1.4-.2-.1z"/>
<path d="M138.6 127.9l.3 .1-.1 1.4-.2-.1zM139.1 127.9l.3 .1-.1 1.4-.2-.1zM139.6 127.9l.3 .1-.1 1.4-.2-.1zM140.1 127.9l.3 .1-.1 1.4-.2-.1zM140.6 127.9l.3 .1-.1 1.4-.2-.1zM141.7 130.8l.8 .1v.9l-.8-.1zM141.7 129.1h.8v.9h-.8zM141.9 126.6h1.4l.1 .2-1.5 .1zM141.9 126.1h1.4l.1 .2-1.5 .1zM141.9 125.6h1.4l.1 .2-1.5 .1zM141.9 125.1h1.4l.1 .2-1.5 .1zM141.9 124.6h1.4l.1 .2-1.5 .1z"/>
<path d="M141.9 124.1h1.4l.1 .2-1.5 .1zM141.9 123.6h1.4l.1 .2-1.5 .1zM141.9 123.1h1.4l.1 .2-1.5 .1zM141.9 122.6h1.4l.1 .2-1.5 .1zM141.9 122.1h1.4l.1 .2-1.5 .1zM141.9 121.6h1.4l.1 .2-1.5 .1zM141.9 121.1h1.4l.1 .2-1.5 .1zM141.9 120.6h1.4l.1 .2-1.5 .1zM141.9 120.1h1.4l.1 .2-1.5 .1zM144.2 130.8l.9 .1-.1 .9-.8-.1zM144.2 129.1h.9l-.1 .9h-.8zM146.9 130.8l.8 .1v.9l-.8-.1z"/>
<path d="M146.9 129.1h.8v.9h-.8zM146.9 120.1h1.4v.2l-1.4 .1zM146.9 120.6h1.4v.2l-1.4 .1zM146.9 121.1h1.4v.2l-1.4 .1zM146.9 121.6h1.4v.2l-1.4 .1zM146.9 122.1h1.4v.2l-1.4 .1zM146.9 122.6h1.4v.2l-1.4 .1zM146.9 123.1h1.4v.2l-1.4 .1zM146.9 123.6h1.4v.2l-1.4 .1zM146.9 124.1h1.4v.2l-1.4 .1zM146.9 124.6h1.4v.2l-1.4 .1zM146.9 125.1h1.4v.2l-1.4 .1z"/>
<path d="M146.9 125.6h1.4v.2l-1.4 .1zM146.9 126.1h1.4v.2l-1.4 .1zM146.9 126.6h1.4v.2l-1.4 .1zM149.4 127.9l.2 .1v1.4l-.3-.1zM149.6 137.3h2.2v1.2h-2.2zM149.6 132.8h2.2v1.2h-2.2zM149.9 127.9l.2 .1v1.4l-.3-.1zM150.4 127.9l.2 .1v1.4l-.3-.1zM150.9 127.9l.2 .1v1.4l-.3-.1zM151.4 127.9l.2 .1v1.4l-.3-.1zM151.9 127.9l.2 .1v1.4l-.3-.1zM152.4 127.9l.2 .1v1.4l-.3-.1z"/>
<path d="M152.9 127.9l.2 .1v1.4l-.3-.1zM153.4 127.9l.2 .1v1.4l-.3-.1zM153.8 135.8h3.1v2.7h-3.1zM153.8 132.7h3.1v2.8h-3.1zM153.9 127.9l.2 .1v1.4l-.3-.1zM154.4 127.9l.2 .1v1.4l-.3-.1zM154.9 127.9l.2 .1v1.4l-.3-.1zM155.4 127.9l.2 .1v1.4l-.3-.1zM155.9 127.9l.2 .1v1.4l-.3-.1zM156.4 127.9l.2 .1v1.4l-.3-.1zM156.9 127.9l.2 .1v1.4l-.3-.1zM157.2 132.7h3v2.8h-3z"/>
<path d="M157.2 135.8h3v2.7h-3zM157.4 127.9l.2 .1v1.4l-.3-.1zM157.9 127.9l.2 .1v1.4l-.3-.1zM158.4 127.9l.2 .1v1.4l-.3-.1zM158.9 127.9l.2 .1v1.4l-.3-.1zM159.4 127.9l.2 .1v1.4l-.3-.1zM159.9 127.9l.2 .1v1.4l-.3-.1zM160.4 127.9l.2 .1v1.4l-.3-.1zM160.9 127.9l.2 .1v1.4l-.3-.1zM161.4 127.9l.2 .1v1.4l-.3-.1zM161.9 127.9l.2 .1v1.4l-.3-.1zM162.4 127.9l.2 .1v1.4l-.3-.1z"/>
<path d="M162.9 127.9l.2 .1v1.4l-.3-.1zM163.4 127.9l.2 .1v1.4l-.3-.1zM163.9 127.9l.2 .1v1.4l-.3-.1zM164.4 127.9l.2 .1v1.4l-.3-.1zM164.9 127.9l.2 .1v1.4l-.3-.1zM165.4 127.9l.2 .1v1.4l-.3-.1zM165.9 127.9l.2 .1v1.4l-.3-.1zM166.4 127.9l.2 .1v1.4l-.3-.1zM166.9 127.9l.2 .1v1.4l-.3-.1zM168.2 126.6h1.4v.2l-1.4 .1zM168.2 126.1h1.4v.2l-1.4 .1zM168.2 125.6h1.4v.2l-1.4 .1z"/>
<path d="M168.2 125.1h1.4v.2l-1.4 .1zM168.2 124.6h1.4v.2l-1.4 .1zM168.2 124.1h1.4v.2l-1.4 .1zM168.2 123.6h1.4v.2l-1.4 .1zM168.2 123.1h1.4v.2l-1.4 .1zM168.2 122.6h1.4v.2l-1.4 .1zM168.2 122.1h1.4v.2l-1.4 .1zM168.2 121.6h1.4v.2l-1.4 .1zM168.2 121.1h1.4v.2l-1.4 .1zM168.2 120.6h1.4v.2l-1.4 .1zM168.2 120.1h1.4v.2l-1.4 .1zM203.9 124.4h7v7h-7z"/>
<path d="M213.1 123.8h1.6v.7h-1.6zM213.1 122.9h1.6v.6h-1.6zM213.1 121.9h1.6v.7h-1.6zM213.2 125.8h.8v.9h-.8zM213.2 127.5l.8 .1v.9l-.8-.1zM212.7 138.5h1.6v1.3h-1.6zM212.7 135.5h1.6v1.3h-1.6zM213 129.3h1.2v.9h-1.2zM213 132.6h1.2v.9h-1.2zM215.8 122.9h1.6v.6h-1.6zM215.8 121.9h1.6v.7h-1.6zM215.8 123.8h1.6v.7h-1.6z"/>
<path d="M216.6 127.5l.9 .1-.1 .9-.8-.1zM216.6 125.8h.9l-.1 .9h-.8zM216.4 130.3h1.3v1h-1.3zM216.4 132.3h1.3v1l-1.3 .1zM216.1 138.5h1.6v1.3h-1.6zM216.1 135.5h1.6v1.3h-1.6zM74 145.5h.9v.8h-.9zM74 143.1h.9v.8h-.9zM75.7 145.5h.9l.1 .8h-1zM75.7 143.1h.9l.1 .8h-1zM78 144.7l1.3 .1v1.6l-1.3-.1zM81 144.7l1.3 .1-.1 1.6-1.2-.1z"/>
<path d="M83.3 144.7l1.3 .1v1.6l-1.3-.1zM81 141h3.6v1.4h-3.6zM86.3 144.7l1.3 .1v1.6l-1.3-.1zM94.7 145.7h.8v.9h-.8zM94.7 144h.8v.9l-.8-.1zM97.2 145.9h2v.7h-2zM97.2 145h2v.6h-2zM97.2 144h2v.7h-2zM97.4 141h3.6v1.4h-3.6zM100.7 144h2v.7h-2zM100.7 145h2v.6h-2zM100.7 145.9h2v.7h-2z"/>
<path d="M104.1 145.7h.8v.9h-.8zM104.1 144h.8v.9l-.8-.1zM105.5 141.3h1.6v1.3h-1.6zM106.5 144h.9l-.1 .9-.8-.1zM106.5 145.7h.9l-.1 .9h-.8zM113.7 140.2h1.2v1h-1.2zM114.2 142.1h1v1.3h-1zM116.2 142.1h1v1.3h-1zM116.6 140.2h1.2l.1 1h-1.3zM119.3 142.6h.9v.8h-.9zM121.1 142.6h.9v.8h-.9zM123.1 142.6h.9l.1 .8h-1z"/>
<path d="M124.9 142.6h.9v.8h-.9zM142.9 140.8h1.5v1.9h-1.5zM142.9 144.9h1.5v1.9h-1.5zM163 140.8h1.5v1.9h-1.5zM163 144.9h1.5v1.9h-1.5zM213.9 142.9h1.7v2.2h-1.7zM217.9 142.9h1.8v2.2h-1.8z"/>
</g>
</svg>
